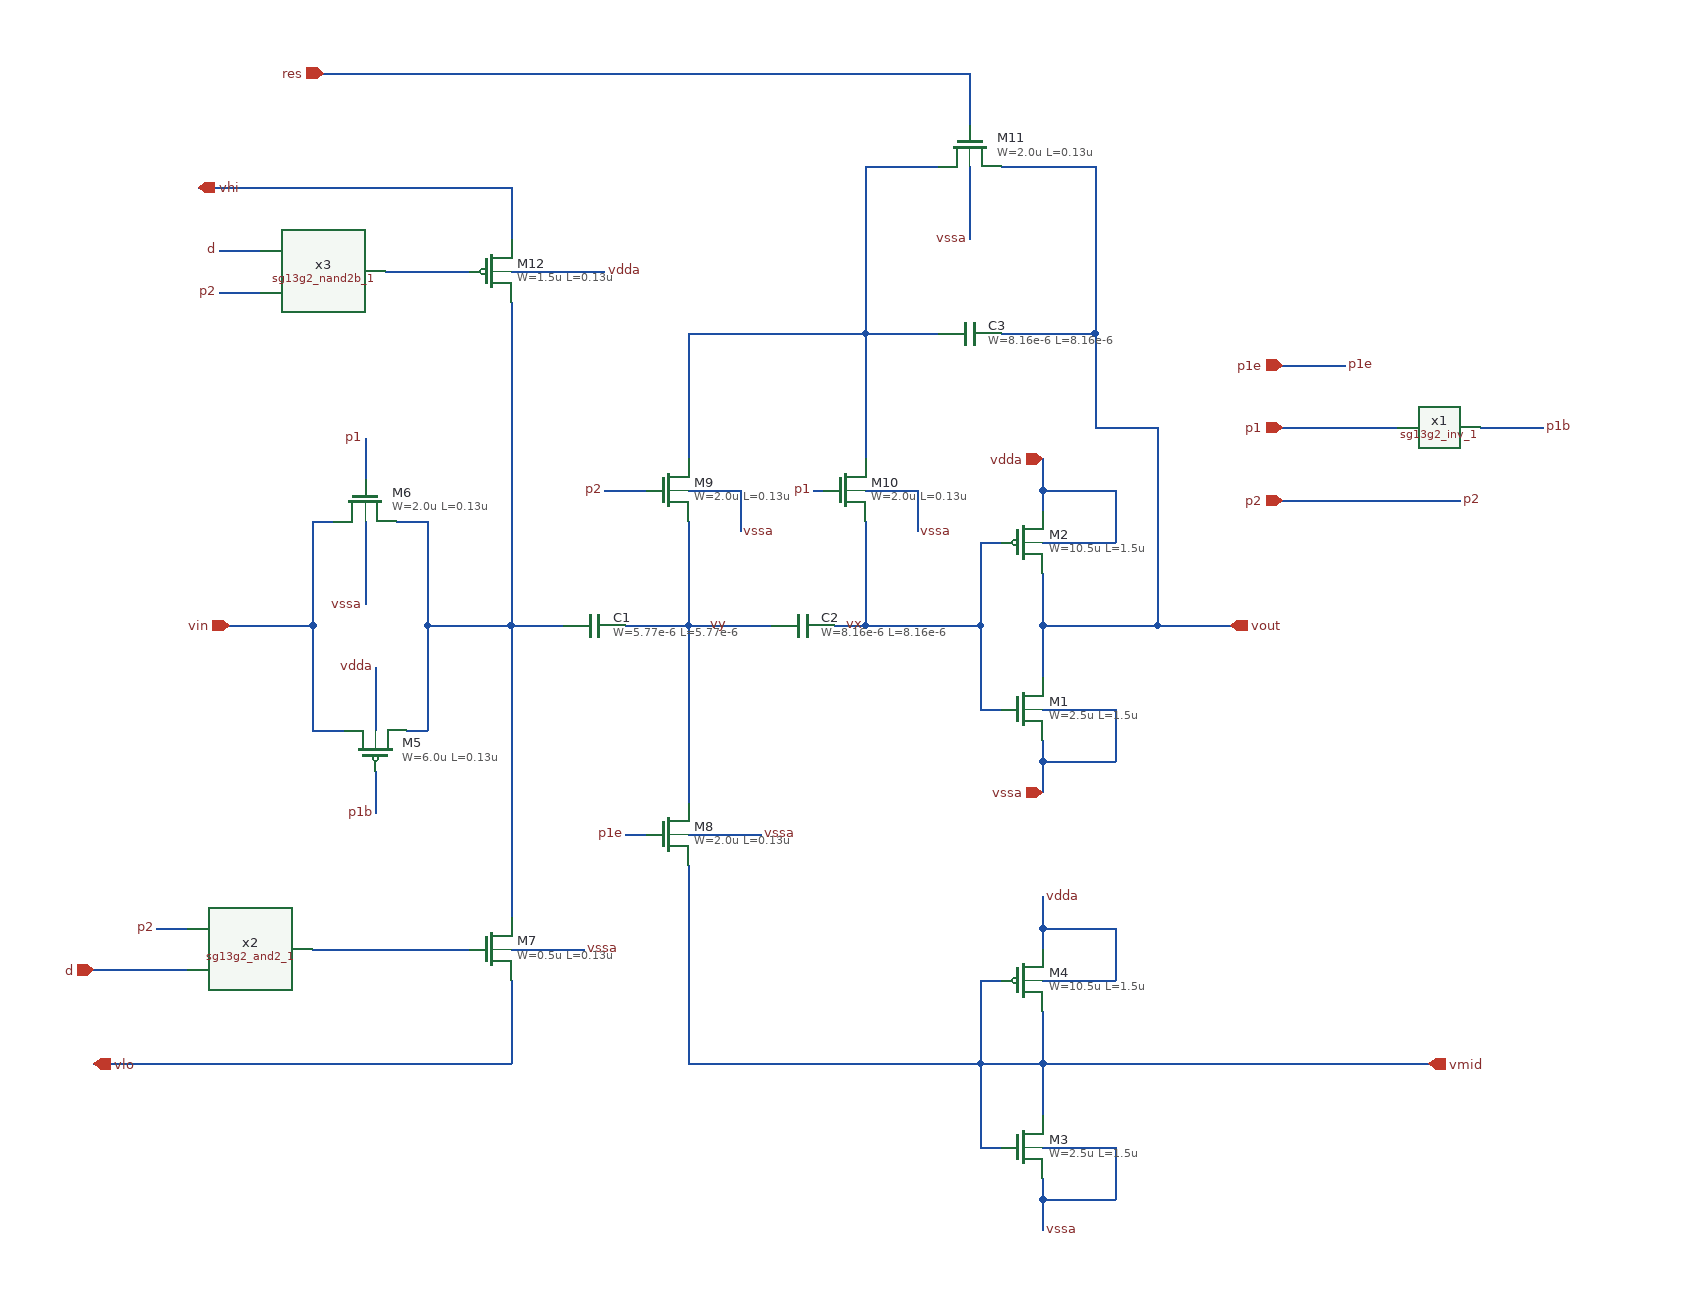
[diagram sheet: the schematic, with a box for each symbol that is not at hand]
v {xschem version=3.4.5 file_version=1.2
}
G {}
K {}
V {}
S {}
E {}
N -190 -50 -190 50 {
lab=vx}
N -220 50 -190 50 {
lab=vx}
N -190 50 -80 50 {
lab=vx}
N -440 -80 -400 -80 {
lab=p2}
N -20 50 -20 100 {
lab=vout}
N -80 -30 -60 -30 {
lab=vx}
N -80 50 -80 130 {
lab=vx}
N -80 130 -60 130 {
lab=vx}
N -20 180 -20 210 {
lab=vssa}
N -20 -80 -20 -60 {
lab=vdda}
N -80 -30 -80 50 {
lab=vx}
N 90 50 160 50 {
lab=vout}
N -20 0 -20 50 {
lab=vout}
N -20 -30 50 -30 {
lab=vdda}
N 50 -80 50 -30 {
lab=vdda}
N -20 -80 50 -80 {
lab=vdda}
N -20 130 50 130 {
lab=vssa}
N 50 130 50 180 {
lab=vssa}
N -20 160 -20 180 {
lab=vssa}
N 90 -140 90 50 {
lab=vout}
N -20 50 90 50 {
lab=vout}
N -190 -230 -190 -110 {
lab=#net1}
N -190 -390 -120 -390 {
lab=#net1}
N -60 -390 30 -390 {
lab=vout}
N 30 -230 30 -140 {
lab=vout}
N 30 -140 90 -140 {
lab=vout}
N -20 180 50 180 {
lab=vssa}
N -720 150 -690 150 {
lab=vin}
N -800 50 -720 50 {
lab=vin}
N -630 150 -610 150 {
lab=#net2}
N -530 50 -530 330 {
lab=#net2}
N -610 50 -530 50 {
lab=#net2}
N -90 -480 -90 -430 {
lab=res}
N -710 -480 -90 -480 {
lab=res}
N -670 -130 -670 -90 {
lab=p1}
N -660 190 -660 230 {
lab=p1b}
N -420 250 -400 250 {
lab=p1e}
N -530 360 -460 360 {
lab=vssa}
N -360 250 -290 250 {
lab=vssa}
N -360 -80 -310 -80 {
lab=vssa}
N -240 -80 -230 -80 {
lab=p1}
N -190 -80 -140 -80 {
lab=vssa}
N -310 -80 -310 -40 {
lab=vssa}
N -140 -80 -140 -40 {
lab=vssa}
N 210 -200 270 -200 {
lab=p1e}
N 210 -140 320 -140 {
lab=p1}
N 210 -70 380 -70 {
lab=p2}
N 400 -140 460 -140 {
lab=p1b}
N -720 -50 -700 -50 {
lab=vin}
N -720 50 -720 150 {
lab=vin}
N -720 -50 -720 50 {
lab=vin}
N -640 -50 -610 -50 {
lab=#net2}
N -610 50 -610 150 {
lab=#net2}
N -610 -50 -610 50 {
lab=#net2}
N -660 90 -660 150 {
lab=vdda}
N -670 -50 -670 30 {
lab=vssa}
N -90 -390 -90 -320 {
lab=vssa}
N -720 360 -570 360 {
lab=#net3}
N -530 390 -530 470 {
lab=vlo}
N -930 470 -530 470 {
lab=vlo}
N -930 380 -840 380 {
lab=d}
N -870 340 -840 340 {
lab=p2}
N -20 470 -20 520 {
lab=vmid}
N -80 390 -60 390 {
lab=#net4}
N -80 470 -80 550 {
lab=#net4}
N -80 550 -60 550 {
lab=#net4}
N -20 600 -20 630 {
lab=vssa}
N -20 340 -20 360 {
lab=vdda}
N -80 390 -80 470 {
lab=#net4}
N -20 420 -20 470 {
lab=vmid}
N -20 390 50 390 {
lab=vdda}
N 50 340 50 390 {
lab=vdda}
N -20 340 50 340 {
lab=vdda}
N -20 550 50 550 {
lab=vssa}
N 50 550 50 600 {
lab=vssa}
N -20 580 -20 600 {
lab=vssa}
N -20 600 50 600 {
lab=vssa}
N -20 470 350 470 {
lab=vmid}
N -20 310 -20 340 {
lab=vdda}
N -20 -110 -20 -80 {
lab=vdda}
N -530 50 -480 50 {
lab=#net2}
N -360 50 -280 50 {
lab=vy}
N -420 50 -360 50 {
lab=vy}
N -360 470 -80 470 {
lab=#net4}
N -360 -50 -360 50 {
lab=vy}
N -190 -230 -120 -230 {
lab=#net1}
N -60 -230 30 -230 {
lab=vout}
N -190 -390 -190 -230 {
lab=#net1}
N 30 -390 30 -230 {
lab=vout}
N -360 -230 -190 -230 {
lab=#net1}
N -360 -230 -360 -110 {
lab=#net1}
N -360 50 -360 220 {
lab=vy}
N -360 280 -360 470 {
lab=#net4}
N -530 -260 -530 50 {
lab=#net2}
N -530 -370 -530 -320 {
lab=vhi}
N -830 -370 -530 -370 {
lab=vhi}
N -650 -290 -570 -290 {
lab=#net5}
N -810 -310 -770 -310 {
lab=d}
N -810 -270 -770 -270 {
lab=p2}
N -530 -290 -440 -290 {
lab=vdda}
N -80 470 -20 470 {}
C {devices/lab_wire.sym} -440 -80 0 0 {name=p14 sig_type=std_logic lab=p2}
C {devices/lab_wire.sym} -190 50 0 0 {name=p17 sig_type=std_logic lab=vx}
C {devices/lab_wire.sym} -320 50 0 0 {name=p18 sig_type=std_logic lab=vy}
C {sg13g2_pr/sg13_lv_nmos.sym} -40 130 2 1 {name=M1
L=1.5u
W=2.5u
ng=1
m=1
model=sg13_lv_nmos
spiceprefix=X
}
C {sg13g2_pr/sg13_lv_pmos.sym} -40 -30 0 0 {name=M2
L=1.5u
W=10.5u
ng=4
m=1
model=sg13_lv_pmos
spiceprefix=X
}
C {sg13g2_pr/sg13_lv_nmos.sym} -670 -70 3 1 {name=M6
L=0.13u
W=2.0u
ng=1
m=1
model=sg13_lv_nmos
spiceprefix=X
}
C {sg13g2_pr/sg13_lv_pmos.sym} -660 170 3 0 {name=M5
L=0.13u
W=6.0u
ng=3
m=1
model=sg13_lv_pmos
spiceprefix=X
}
C {sg13g2_pr/sg13_lv_nmos.sym} -550 360 2 1 {name=M7
L=0.13u
W=0.5u
ng=1
m=1
model=sg13_lv_nmos
spiceprefix=X
}
C {sg13g2_pr/sg13_lv_nmos.sym} -380 250 2 1 {name=M8
L=0.13u
W=2.0u
ng=1
m=1
model=sg13_lv_nmos
spiceprefix=X
}
C {sg13g2_pr/sg13_lv_nmos.sym} -380 -80 2 1 {name=M9
L=0.13u
W=2.0u
ng=1
m=1
model=sg13_lv_nmos
spiceprefix=X
}
C {sg13g2_pr/sg13_lv_nmos.sym} -210 -80 2 1 {name=M10
L=0.13u
W=2.0u
ng=1
m=1
model=sg13_lv_nmos
spiceprefix=X
}
C {sg13g2_pr/sg13_lv_nmos.sym} -90 -410 3 1 {name=M11
L=0.13u
W=2.0u
ng=1
m=1
model=sg13_lv_nmos
spiceprefix=X
}
C {devices/lab_wire.sym} -240 -80 0 0 {name=p4 sig_type=std_logic lab=p1}
C {devices/lab_wire.sym} -420 250 0 0 {name=p5 sig_type=std_logic lab=p1e}
C {devices/lab_wire.sym} -660 230 0 0 {name=p7 sig_type=std_logic lab=p1b}
C {devices/lab_wire.sym} -670 -130 0 0 {name=p8 sig_type=std_logic lab=p1}
C {devices/ipin.sym} -800 50 0 0 {name=p9 lab=vin}
C {devices/ipin.sym} -710 -480 0 0 {name=p1 lab=res}
C {devices/iopin.sym} -930 470 0 1 {name=p10 lab=vlo}
C {devices/iopin.sym} -20 -110 0 0 {name=p11 lab=vdda}
C {devices/opin.sym} 160 50 0 0 {name=p13 lab=vout}
C {devices/ipin.sym} 210 -200 0 0 {name=p2 lab=p1e}
C {devices/ipin.sym} 210 -140 0 0 {name=p3 lab=p1}
C {devices/ipin.sym} 210 -70 0 0 {name=p12 lab=p2}
C {sg13g2_stdcells/sg13g2_inv_1.sym} 360 -140 0 0 {name=x1 VDD=VDD VSS=VSS prefix=sg13g2_ }
C {devices/lab_wire.sym} 460 -140 0 1 {name=p15 sig_type=std_logic lab=p1b}
C {devices/lab_wire.sym} 270 -200 0 1 {name=p16 sig_type=std_logic lab=p1e}
C {devices/lab_wire.sym} 380 -70 0 1 {name=p19 sig_type=std_logic lab=p2}
C {devices/lab_wire.sym} -660 90 0 0 {name=p20 sig_type=std_logic lab=vdda}
C {devices/iopin.sym} -20 210 0 0 {name=p21 lab=vssa}
C {devices/lab_wire.sym} -290 250 0 1 {name=p22 sig_type=std_logic lab=vssa}
C {devices/lab_wire.sym} -460 360 0 1 {name=p23 sig_type=std_logic lab=vssa}
C {sg13g2_stdcells/sg13g2_and2_1.sym} -780 360 0 0 {name=x2 VDD=VDD VSS=VSS prefix=sg13g2_ }
C {devices/ipin.sym} -930 380 0 0 {name=p6 lab=d}
C {devices/lab_wire.sym} -870 340 0 0 {name=p24 sig_type=std_logic lab=p2}
C {sg13g2_pr/cap_cmim.sym} -450 50 1 0 {name=C1 model=cap_cmim W=5.77e-6 L=5.77e-6 MF=1 spiceprefix=X}
C {sg13g2_pr/sg13_lv_nmos.sym} -40 550 2 1 {name=M3
L=1.5u
W=2.5u
ng=1
m=1
model=sg13_lv_nmos
spiceprefix=X
}
C {sg13g2_pr/sg13_lv_pmos.sym} -40 390 0 0 {name=M4
L=1.5u
W=10.5u
ng=4
m=1
model=sg13_lv_pmos
spiceprefix=X
}
C {devices/opin.sym} 350 470 0 0 {name=p27 lab=vmid}
C {devices/lab_wire.sym} -20 310 0 1 {name=p25 sig_type=std_logic lab=vdda}
C {devices/lab_wire.sym} -20 630 0 1 {name=p26 sig_type=std_logic lab=vssa}
C {devices/lab_wire.sym} -310 -40 0 1 {name=p28 sig_type=std_logic lab=vssa}
C {devices/lab_wire.sym} -140 -40 0 1 {name=p29 sig_type=std_logic lab=vssa}
C {sg13g2_pr/cap_cmim.sym} -250 50 1 0 {name=C2 model=cap_cmim W=8.16e-6 L=8.16e-6 MF=1 spiceprefix=X}
C {sg13g2_pr/cap_cmim.sym} -90 -230 1 0 {name=C3 model=cap_cmim W=8.16e-6 L=8.16e-6 MF=1 spiceprefix=X}
C {devices/lab_wire.sym} -90 -320 0 0 {name=p30 sig_type=std_logic lab=vssa}
C {sg13g2_pr/sg13_lv_pmos.sym} -550 -290 0 0 {name=M12
L=0.13u
W=1.5u
ng=1
m=1
model=sg13_lv_pmos
spiceprefix=X
}
C {sg13g2_stdcells/sg13g2_nand2b_1.sym} -710 -290 0 0 {name=x3 VDD=VDD VSS=VSS prefix=sg13g2_ }
C {devices/lab_wire.sym} -810 -270 0 0 {name=p31 sig_type=std_logic lab=p2}
C {devices/lab_wire.sym} -810 -310 0 0 {name=p32 sig_type=std_logic lab=d}
C {devices/iopin.sym} -830 -370 0 1 {name=p33 lab=vhi}
C {devices/lab_wire.sym} -670 30 0 0 {name=p34 sig_type=std_logic lab=vssa}
C {devices/lab_wire.sym} -440 -290 0 1 {name=p35 sig_type=std_logic lab=vdda}
